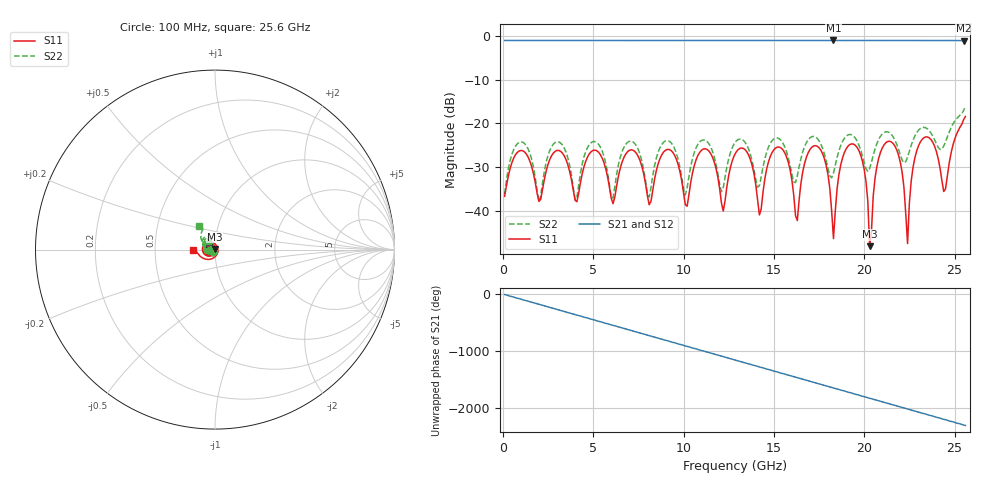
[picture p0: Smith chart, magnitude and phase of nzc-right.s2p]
! scikit-rf 1.8.0 golden reference; NZC forced split impedance 50 ohm
# Hz S RI R 50
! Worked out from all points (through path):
!   256 points, 100 MHz to 25.6 GHz, reference 50 ohm
!   highest |S21| = -1.00 dB at 18.3 GHz (marker M1); lowest = -1.1 dB at 25.5 GHz (marker M2)
!   group delay of S21, straight-line fit = 250 ps
!   lowest |S11| = -48.1 dB at 20.3 GHz (marker M3), VSWR 1.01, Z = 49.8 + j0.35 ohm
!   |S11| at or under -10 dB: start of sweep to end of sweep
!   |S22| runs from -37.9 to -16.1 dB; largest |S21 - S12| = 0
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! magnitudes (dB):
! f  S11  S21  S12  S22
! 100 MHz  -36.7  -1.0  -1.0  -36.1
! 900 MHz  -26.3  -1.0  -1.0  -24.3
! 2 GHz  -37.8  -1.0  -1.0  -37.9
! 4.4 GHz  -31.4  -1.0  -1.0  -29.1
! 8.6 GHz  -29.2  -1.0  -1.0  -26.5
! 10.2 GHz  -38.9  -1.0  -1.0  -34.8
! 11.3 GHz  -25.9  -1.0  -1.0  -24.1
! 12.2 GHz  -40.0  -1.0  -1.0  -34.7
! 12.9 GHz  -26.6  -1.0  -1.0  -24.1
! 14.2 GHz  -40.9  -1.0  -1.0  -34.2
! 15.5 GHz  -26.0  -1.0  -1.0  -24.5
! 16.3 GHz  -42.2  -1.0  -1.0  -31.9
! 17.1 GHz  -25.4  -1.0  -1.0  -23.0
! 18.3 GHz  -46.3  -1.0  -1.0  -31.3
! 19.4 GHz  -24.7  -1.0  -1.0  -22.9
! 20.3 GHz  -48.1  -1.0  -1.0  -30.3
! 21.4 GHz  -24.1  -1.0  -1.0  -22.1
! 22.4 GHz  -47.5  -1.0  -1.0  -27.7
! 23 GHz  -25.2  -1.0  -1.0  -21.6
! 24.4 GHz  -35.5  -1.0  -1.0  -25.2
! 25.5 GHz  -19.1  -1.1  -1.1  -17.0
! 25.6 GHz  -18.4  -1.0  -1.0  -16.1
